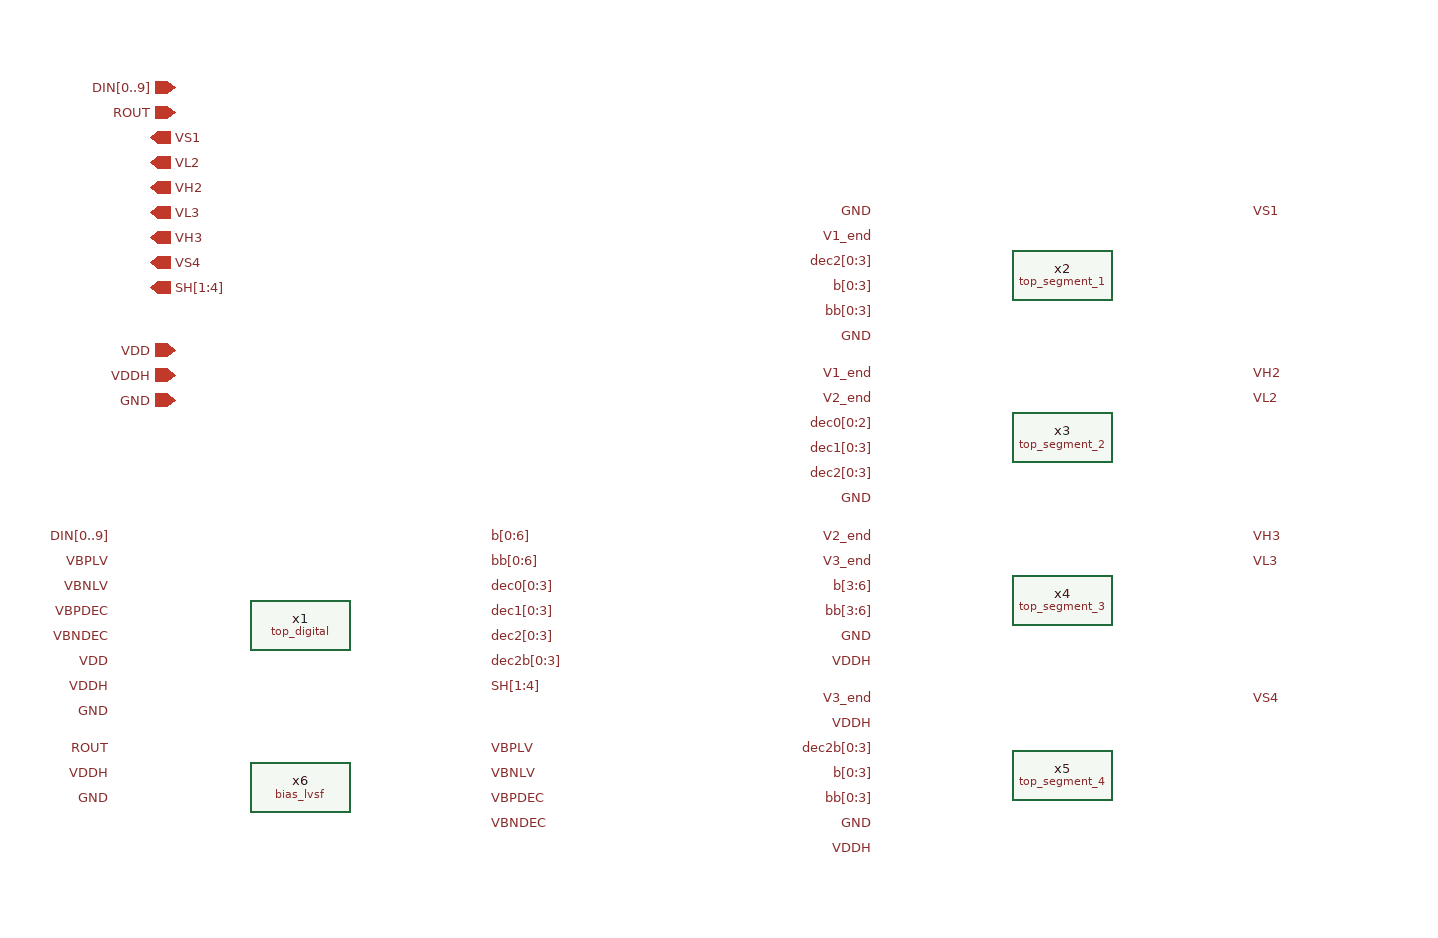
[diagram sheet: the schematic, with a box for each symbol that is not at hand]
v {xschem version=3.4.8RC file_version=1.2}
G {}
K {}
V {}
S {}
E {}
C {top_digital.sym} 260 -250 0 0 {name=x1}
C {top_segment_1.sym} 870 -530 0 0 {name=x2}
C {top_segment_2.sym} 870 -400 0 0 {name=x3}
C {top_segment_3.sym} 870 -270 0 0 {name=x4}
C {top_segment_4.sym} 870 -130 0 0 {name=x5}
C {devices/ipin.sym} 160 -430 0 0 {name=p30 lab=GND}
C {devices/ipin.sym} 160 -470 0 0 {name=p31 lab=VDD}
C {devices/ipin.sym} 160 -450 0 0 {name=p78 lab=VDDH}
C {devices/ipin.sym} 160 -680 0 0 {name=p122 lab=DIN[0..9]}
C {devices/opin.sym} 140 -520 0 0 {name=p6 lab=SH[1:4]}
C {devices/lab_pin.sym} 410 -320 0 1 {name=p137 sig_type=std_logic lab=b[0:6]}
C {devices/lab_pin.sym} 110 -320 0 0 {name=p138 sig_type=std_logic lab=DIN[0..9]}
C {devices/lab_pin.sym} 110 -220 0 0 {name=p139 sig_type=std_logic lab=VDD}
C {devices/lab_pin.sym} 110 -180 0 0 {name=p140 sig_type=std_logic lab=GND}
C {bias_lvsf.sym} 260 -120 0 0 {name=x6}
C {devices/lab_pin.sym} 110 -200 0 0 {name=p4 sig_type=std_logic lab=VDDH}
C {devices/lab_pin.sym} 110 -300 0 0 {name=p7 sig_type=std_logic lab=VBPLV}
C {devices/lab_pin.sym} 110 -280 0 0 {name=p8 sig_type=std_logic lab=VBNLV}
C {devices/lab_pin.sym} 110 -260 0 0 {name=p9 sig_type=std_logic lab=VBPDEC}
C {devices/lab_pin.sym} 110 -240 0 0 {name=p10 sig_type=std_logic lab=VBNDEC}
C {devices/lab_pin.sym} 110 -150 0 0 {name=p11 sig_type=std_logic lab=ROUT}
C {devices/lab_pin.sym} 110 -110 0 0 {name=p13 sig_type=std_logic lab=GND}
C {devices/lab_pin.sym} 1020 -580 0 1 {name=p14 sig_type=std_logic lab=VS1}
C {devices/lab_pin.sym} 1020 -190 0 1 {name=p15 sig_type=std_logic lab=VS4}
C {devices/lab_pin.sym} 1020 -450 0 1 {name=p16 sig_type=std_logic lab=VH2}
C {devices/lab_pin.sym} 1020 -430 0 1 {name=p17 sig_type=std_logic lab=VL2}
C {devices/lab_pin.sym} 1020 -320 0 1 {name=p18 sig_type=std_logic lab=VH3}
C {devices/lab_pin.sym} 1020 -300 0 1 {name=p19 sig_type=std_logic lab=VL3}
C {devices/lab_pin.sym} 720 -580 0 0 {name=p20 sig_type=std_logic lab=GND}
C {devices/lab_pin.sym} 720 -450 0 0 {name=p23 sig_type=std_logic lab=V1_end}
C {devices/lab_pin.sym} 720 -560 0 0 {name=p24 sig_type=std_logic lab=V1_end}
C {devices/lab_pin.sym} 720 -430 0 0 {name=p25 sig_type=std_logic lab=V2_end}
C {devices/lab_pin.sym} 720 -320 0 0 {name=p26 sig_type=std_logic lab=V2_end}
C {devices/lab_pin.sym} 720 -300 0 0 {name=p27 sig_type=std_logic lab=V3_end}
C {devices/lab_pin.sym} 720 -190 0 0 {name=p22 sig_type=std_logic lab=V3_end}
C {devices/lab_pin.sym} 720 -240 0 0 {name=p32 sig_type=std_logic lab=GND}
C {devices/lab_pin.sym} 720 -350 0 0 {name=p33 sig_type=std_logic lab=GND}
C {devices/lab_pin.sym} 720 -480 0 0 {name=p34 sig_type=std_logic lab=GND}
C {devices/lab_pin.sym} 720 -90 0 0 {name=p35 sig_type=std_logic lab=GND}
C {devices/lab_pin.sym} 410 -150 0 1 {name=p36 sig_type=std_logic lab=VBPLV}
C {devices/lab_pin.sym} 410 -130 0 1 {name=p37 sig_type=std_logic lab=VBNLV}
C {devices/lab_pin.sym} 410 -110 0 1 {name=p38 sig_type=std_logic lab=VBPDEC}
C {devices/lab_pin.sym} 410 -90 0 1 {name=p39 sig_type=std_logic lab=VBNDEC}
C {devices/lab_pin.sym} 410 -300 0 1 {name=p40 sig_type=std_logic lab=bb[0:6]}
C {devices/lab_pin.sym} 410 -280 0 1 {name=p41 sig_type=std_logic lab=dec0[0:3]}
C {devices/lab_pin.sym} 410 -260 0 1 {name=p42 sig_type=std_logic lab=dec1[0:3]}
C {devices/lab_pin.sym} 410 -240 0 1 {name=p43 sig_type=std_logic lab=dec2[0:3]}
C {devices/lab_pin.sym} 410 -220 0 1 {name=p44 sig_type=std_logic lab=dec2b[0:3]}
C {devices/lab_pin.sym} 410 -200 0 1 {name=p45 sig_type=std_logic lab=SH[1:4]}
C {devices/lab_pin.sym} 720 -410 0 0 {name=p46 sig_type=std_logic lab=dec0[0:2]}
C {devices/lab_pin.sym} 720 -390 0 0 {name=p47 sig_type=std_logic lab=dec1[0:3]}
C {devices/lab_pin.sym} 720 -370 0 0 {name=p48 sig_type=std_logic lab=dec2[0:3]}
C {devices/lab_pin.sym} 720 -280 0 0 {name=p49 sig_type=std_logic lab=b[3:6]}
C {devices/lab_pin.sym} 720 -260 0 0 {name=p50 sig_type=std_logic lab=bb[3:6]}
C {devices/lab_pin.sym} 720 -130 0 0 {name=p51 sig_type=std_logic lab=b[0:3]}
C {devices/lab_pin.sym} 720 -150 0 0 {name=p53 sig_type=std_logic lab=dec2b[0:3]}
C {devices/lab_pin.sym} 720 -110 0 0 {name=p52 sig_type=std_logic lab=bb[0:3]}
C {devices/lab_pin.sym} 720 -540 0 0 {name=p54 sig_type=std_logic lab=dec2[0:3]}
C {devices/lab_pin.sym} 720 -520 0 0 {name=p55 sig_type=std_logic lab=b[0:3]}
C {devices/lab_pin.sym} 720 -500 0 0 {name=p56 sig_type=std_logic lab=bb[0:3]}
C {devices/opin.sym} 140 -640 0 0 {name=p1 lab=VS1}
C {devices/opin.sym} 140 -600 0 0 {name=p2 lab=VH2}
C {devices/opin.sym} 140 -620 0 0 {name=p3 lab=VL2}
C {devices/opin.sym} 140 -560 0 0 {name=p5 lab=VH3}
C {devices/opin.sym} 140 -580 0 0 {name=p58 lab=VL3}
C {devices/opin.sym} 140 -540 0 0 {name=p59 lab=VS4}
C {devices/ipin.sym} 160 -660 0 0 {name=p60 lab=ROUT}
C {devices/lab_pin.sym} 110 -130 0 0 {name=p12 sig_type=std_logic lab=VDDH}
C {devices/lab_pin.sym} 720 -220 0 0 {name=p21 sig_type=std_logic lab=VDDH}
C {devices/lab_pin.sym} 720 -170 0 0 {name=p28 sig_type=std_logic lab=VDDH}
C {devices/lab_pin.sym} 720 -70 0 0 {name=p29 sig_type=std_logic lab=VDDH}
